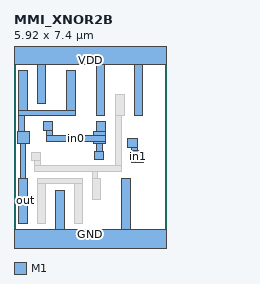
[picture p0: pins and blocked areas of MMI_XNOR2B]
MACRO MMI_XNOR2B
	CLASS CORE ;
	FOREIGN MMI_XNOR2B 0 0 ;
	SIZE 5.92 BY 7.4 ;
	SYMMETRY X Y ;
	SITE CORE1 ;
	PIN out
		DIRECTION output ;
		USE SIGNAL ;
		PORT
			LAYER M1 ;
			RECT 0.18 5.14 0.52 6.67 ;
			LAYER M1 ;
			RECT 2.05 5.14 2.39 6.67 ;
			LAYER M1 ;
			RECT 0.18 4.91 2.39 5.14 ;
			LAYER M1 ;
			RECT 0.18 4.295 0.41 4.91 ;
			LAYER M1 ;
			RECT 0.145 3.845 0.595 4.295 ;
			LAYER M1 ;
			RECT 0.235 2.49 0.465 3.845 ;
			LAYER M1 ;
			RECT 0.18 0.73 0.52 2.49 ;
		END
		AntennaDiffArea 2.76 ;
	END out
	PIN in1
		DIRECTION input ;
		USE SIGNAL ;
		PORT
			LAYER M1 ;
			RECT 4.425 3.695 4.815 4.035 ;
			LAYER M1 ;
			RECT 4.585 3.555 4.815 3.695 ;
			LAYER M1 ;
			RECT 4.585 3.105 5.035 3.555 ;
		END
		AntennaGateArea 1.3248 ;
	END in1
	PIN GND
		DIRECTION inout ;
		USE GROUND ;
		PORT
			LAYER M1 ;
			RECT 1.62 0.5 1.96 2.01 ;
			LAYER M1 ;
			RECT 4.19 0.5 4.53 2.49 ;
			LAYER M1 ;
			RECT 0 -0.5 5.92 0.5 ;
		END
	END GND
	PIN VDD
		DIRECTION inout ;
		USE POWER ;
		PORT
			LAYER M1 ;
			RECT 0 6.9 5.92 7.9 ;
			LAYER M1 ;
			RECT 0.9 5.39 1.24 6.9 ;
			LAYER M1 ;
			RECT 3.2 4.91 3.54 6.9 ;
			LAYER M1 ;
			RECT 4.68 4.91 5.02 6.9 ;
		END
	END VDD
	PIN in0
		DIRECTION input ;
		USE SIGNAL ;
		PORT
			LAYER M1 ;
			RECT 1.14 4.335 1.48 4.675 ;
			LAYER M1 ;
			RECT 1.25 4.135 1.48 4.335 ;
			LAYER M1 ;
			RECT 3.205 4.295 3.545 4.675 ;
			LAYER M1 ;
			RECT 3.105 4.135 3.555 4.295 ;
			LAYER M1 ;
			RECT 1.25 3.905 3.555 4.135 ;
			LAYER M1 ;
			RECT 3.105 3.845 3.555 3.905 ;
			LAYER M1 ;
			RECT 3.23 3.54 3.46 3.845 ;
			LAYER M1 ;
			RECT 3.145 3.2 3.485 3.54 ;
		END
		AntennaGateArea 1.3248 ;
	END in0
	OBS
		LAYER M1 ;
		RECT 3.96 4.91 4.3 5.75 ;
		LAYER M1 ;
		RECT 0.695 3.16 1.035 3.5 ;
		LAYER M1 ;
		RECT 0.805 2.965 1.035 3.16 ;
		LAYER M1 ;
		RECT 3.96 2.965 4.19 4.91 ;
		LAYER M1 ;
		RECT 0.805 2.735 4.19 2.965 ;
		LAYER M1 ;
		RECT 3.04 2.49 3.27 2.735 ;
		LAYER M1 ;
		RECT 0.9 2.26 2.68 2.49 ;
		LAYER M1 ;
		RECT 0.9 0.73 1.24 2.26 ;
		LAYER M1 ;
		RECT 2.34 0.73 2.68 2.26 ;
		LAYER M1 ;
		RECT 3.04 1.65 3.38 2.49 ;
	END
END MMI_XNOR2B
